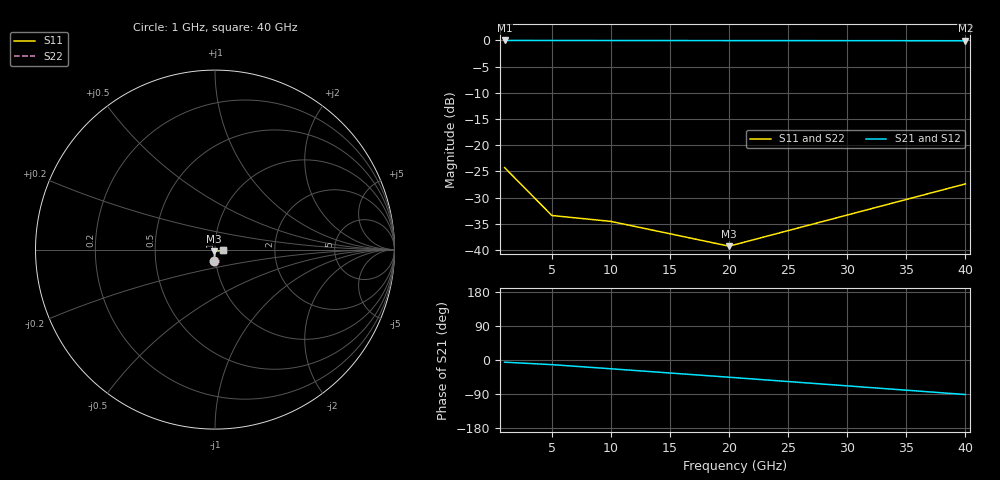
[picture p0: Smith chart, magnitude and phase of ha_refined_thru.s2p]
! Generated by circuitRF - EM: Palace
! circuitRF-EM setup: ha_refined_thru Palace
! circuitRF-EM layout: ha_refined_thru.c3d
! circuitRF-EM written: 2026-11-04 15:47:28Z
! circuitRF-EM geometry: 4b96cc38279ac78e
! circuitRF-EM mesh: 5f7b40af5b6dd3d3
! circuitRF-EM ports: 078653bfccbb427f
! circuitRF-EM model: Palace 0.18.1 (0dc74cd, schema 1-7-0)
! Port[1] = P1
! Port[2] = P2
! circuitRF-EM port 1: 'port/1' from 'airbox/zmin' to 'metal1', wave (mode 1), 50 Ohm: Palace's S is referred to the mode's own impedance Z_PV, renormalised here to 50 Ohm; reference plane 0 um into the structure from the port face
! circuitRF-EM port 2: 'port/2' from 'airbox/zmin' to 'metal1', wave (mode 1), 50 Ohm: Palace's S is referred to the mode's own impedance Z_PV, renormalised here to 50 Ohm; reference plane 0 um into the structure from the port face
! circuitRF-EM 3D mesh: 21,330 elements initially, 21,330 finally, 0 adaptive pass(es), element order 2
! circuitRF-EM 3D operating temperature: 20 C
! circuitRF-EM 3D run: preset Standard; 21330 -> 21330 tetrahedra; 148776 unknowns; 0 refinement pass(es); 5 frequency sample(s)
! circuitRF-EM 3D run cost: wall 82 s; Palace peak memory 2.8 GB
! circuitRF-EM 3D DC row: circuitRF conduction solve of the conductors, 370 elements, 0.18 s; ports as terminal pairs
! circuitRF-EM: re-running the EM setup rewrites this file. If circuitRF reports it as stale, the layout's cross-section changed after this file was written.
# GHz S RI R 50
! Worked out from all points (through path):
!   5 points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, 1 GHz to 40 GHz, reference 50 ohm
!   highest |S21| = -0.01 dB at 1 GHz (marker M1); lowest = -0.1 dB at 40 GHz (marker M2)
!   lowest |S11| = -39.2 dB at 20 GHz (marker M3), VSWR 1.02, Z = 49.5 - j0.976 ohm
!   |S11| at or under -10 dB: start of sweep to end of sweep
!   |S22| runs from -39.2 to -24.3 dB; largest |S21 - S12| = 3.2e-07
1  -0.00316 -0.0611  0.9937 -0.0999  0.9937 -0.0999  -0.00316 -0.0611
5  -0.00271 -0.0212  0.9754 -0.2117  0.9754 -0.2117  -0.00271 -0.0212
10  -0.00499 -0.0181  0.9167 -0.3924  0.9167 -0.3924  -0.00498 -0.0181
20  -0.00467 -0.00985  0.698 -0.7097  0.698 -0.7097  -0.00467 -0.00986
40  0.0425 -0.00491  -0.0189 -0.9919  -0.0189 -0.9919  0.0425 -0.00485
